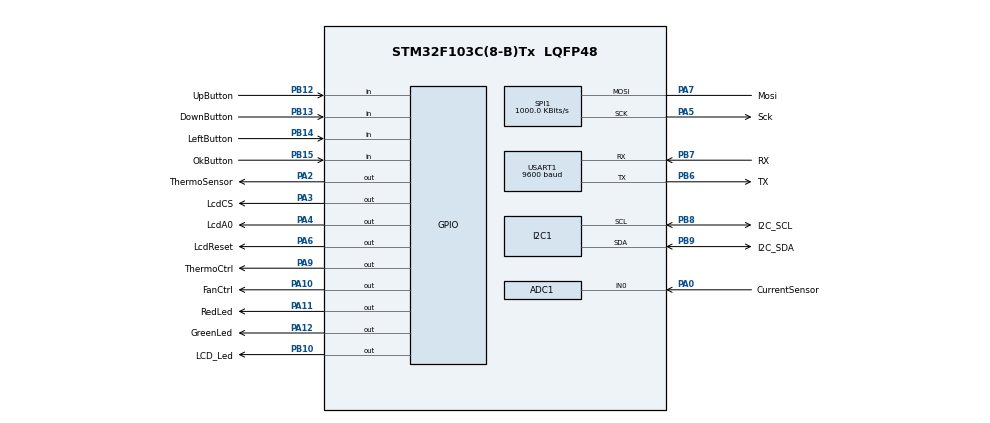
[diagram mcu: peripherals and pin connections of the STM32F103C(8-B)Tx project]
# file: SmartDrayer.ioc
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ADC1.Channel-0\#ChannelRegularConversion=ADC_CHANNEL_0
ADC1.NbrOfConversionFlag=1
ADC1.Rank-0\#ChannelRegularConversion=1
ADC1.SamplingTime-0\#ChannelRegularConversion=ADC_SAMPLETIME_1CYCLE_5
ADC1.master=1
Mcu.Family=STM32F1
Mcu.Name=STM32F103C(8-B)Tx
Mcu.Package=LQFP48
NVIC.PriorityGroup=NVIC_PRIORITYGROUP_4
NVIC.USART1_IRQn=true\:0\:0\:false\:false\:true\:true\:true
PA0-WKUP.GPIO_Label=CurrentSensor
PA0-WKUP.Signal=ADCx_IN0
PA10.GPIO_Label=FanCtrl
PA10.GPIO_Speed=GPIO_SPEED_FREQ_HIGH
PA10.Signal=GPIO_Output
PA11.GPIO_Label=RedLed
PA11.Signal=GPIO_Output
PA12.GPIO_Label=GreenLed
PA12.Signal=GPIO_Output
PA13.GPIO_Label=SWDIO
PA13.Mode=Serial_Wire
PA13.Signal=SYS_JTMS-SWDIO
PA14.GPIO_Label=SWCLK
PA14.Mode=Serial_Wire
PA14.Signal=SYS_JTCK-SWCLK
PA2.GPIO_Label=ThermoSensor
PA2.GPIO_Speed=GPIO_SPEED_FREQ_HIGH
PA2.PinState=GPIO_PIN_SET
PA2.Signal=GPIO_Output
PA3.GPIO_Label=LcdCS
PA3.GPIO_Speed=GPIO_SPEED_FREQ_HIGH
PA3.PinState=GPIO_PIN_SET
PA3.Signal=GPIO_Output
PA4.GPIO_Label=LcdA0
PA4.GPIO_Speed=GPIO_SPEED_FREQ_HIGH
PA4.Signal=GPIO_Output
PA5.GPIO_Label=Sck
PA5.Mode=Simplex_Bidirectional_Master
PA5.Signal=SPI1_SCK
PA6.GPIO_Label=LcdReset
PA6.GPIO_Speed=GPIO_SPEED_FREQ_HIGH
PA6.Signal=GPIO_Output
PA7.GPIO_Label=Mosi
PA7.Mode=Simplex_Bidirectional_Master
PA7.Signal=SPI1_MOSI
PA9.GPIO_Label=ThermoCtrl
PA9.Signal=GPIO_Output
PB10.GPIO_Label=LCD_Led
PB10.GPIO_Speed=GPIO_SPEED_FREQ_MEDIUM
PB10.Signal=GPIO_Output
PB12.GPIO_Label=UpButton
PB12.GPIO_PuPd=GPIO_PULLUP
PB12.Signal=GPIO_Input
PB13.GPIO_Label=DownButton
PB13.GPIO_PuPd=GPIO_PULLUP
PB13.Signal=GPIO_Input
PB14.GPIO_Label=LeftButton
PB14.GPIO_PuPd=GPIO_PULLUP
PB14.Signal=GPIO_Input
PB15.GPIO_Label=OkButton
PB15.GPIO_PuPd=GPIO_PULLUP
PB15.Signal=GPIO_Input
PB6.GPIO_Label=TX
PB6.Mode=Asynchronous
PB6.Signal=USART1_TX
PB7.GPIO_Label=RX
PB7.Mode=Asynchronous
PB7.Signal=USART1_RX
PB8.GPIO_Label=I2C_SCL
PB8.Mode=I2C
PB8.Signal=I2C1_SCL
PB9.GPIO_Label=I2C_SDA
PB9.Mode=I2C
PB9.Signal=I2C1_SDA
ProjectManager.HeapSize=0x200
ProjectManager.StackSize=0x400
ProjectManager.TargetToolchain=STM32CubeIDE
RCC.ADCPresc=RCC_ADCPCLK2_DIV6
RCC.AHBFreq_Value=64000000
RCC.APB1CLKDivider=RCC_HCLK_DIV2
RCC.APB1Freq_Value=32000000
RCC.APB1TimFreq_Value=64000000
RCC.APB2Freq_Value=64000000
RCC.APB2TimFreq_Value=64000000
RCC.HCLKFreq_Value=64000000
RCC.PLLMUL=RCC_PLL_MUL16
RCC.SYSCLKFreq_VALUE=64000000
RCC.SYSCLKSource=RCC_SYSCLKSOURCE_PLLCLK
RCC.USBFreq_Value=64000000
SH.ADCx_IN0.0=ADC1_IN0,IN0
SPI1.BaudRatePrescaler=SPI_BAUDRATEPRESCALER_64
SPI1.CalculateBaudRate=1000.0 KBits/s
SPI1.Direction=SPI_DIRECTION_1LINE
SPI1.Mode=SPI_MODE_MASTER
SPI1.VirtualType=VM_MASTER
TIM2.Period=65535 - 1
USART1.BaudRate=9600
USART1.VirtualMode=VM_ASYNC
VP_TIM2_VS_ClockSourceINT.Mode=Internal
board=custom

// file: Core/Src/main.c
/* USER CODE BEGIN Header */
/**
  ******************************************************************************
  * @file           : main.c
  * @brief          : Main program body
  ******************************************************************************
  * @attention
  *
  * <h2><center>&copy; Copyright (c) 2020 STMicroelectronics.
  * All rights reserved.</center></h2>
  *
  * This software component is licensed by ST under BSD 3-Clause license,
  * the "License"; You may not use this file except in compliance with the
  * License. You may obtain a copy of the License at:
  *                        opensource.org/licenses/BSD-3-Clause
  *
  ******************************************************************************
  */
/* USER CODE END Header */
#include "main.h"
#include "adc.h"
#include "i2c.h"
#include "spi.h"
#include "tim.h"
#include "usart.h"
#include "gpio.h"
//#include "Display.h"
//
//ST7920_LCD Display;

void SystemClock_Config(void);

int main(void)
{

  /* MCU Configuration--------------------------------------------------------*/

  /* Reset of all peripherals, Initializes the Flash interface and the Systick. */
  HAL_Init();

  /* Configure the system clock */
  SystemClock_Config();

  /* Initialize all configured peripherals */
  MX_GPIO_Init();
  MX_ADC1_Init();
  MX_I2C1_Init();
  MX_SPI1_Init();
  MX_TIM2_Init();
  MX_USART1_UART_Init();

  /* Infinite loop */
  while (1)
  {

  }
}

void SystemClock_Config(void)
{
  RCC_OscInitTypeDef RCC_OscInitStruct = {0};
  RCC_ClkInitTypeDef RCC_ClkInitStruct = {0};
  RCC_PeriphCLKInitTypeDef PeriphClkInit = {0};

  /** Initializes the RCC Oscillators according to the specified parameters
  * in the RCC_OscInitTypeDef structure.
  */
  RCC_OscInitStruct.OscillatorType = RCC_OSCILLATORTYPE_HSI;
  RCC_OscInitStruct.HSIState = RCC_HSI_ON;
  RCC_OscInitStruct.HSICalibrationValue = RCC_HSICALIBRATION_DEFAULT;
  RCC_OscInitStruct.PLL.PLLState = RCC_PLL_ON;
  RCC_OscInitStruct.PLL.PLLSource = RCC_PLLSOURCE_HSI_DIV2;
  RCC_OscInitStruct.PLL.PLLMUL = RCC_PLL_MUL6;
  if (HAL_RCC_OscConfig(&RCC_OscInitStruct) != HAL_OK)
  {
    Error_Handler();
  }
  /** Initializes the CPU, AHB and APB buses clocks
  */
  RCC_ClkInitStruct.ClockType = RCC_CLOCKTYPE_HCLK|RCC_CLOCKTYPE_SYSCLK
                              |RCC_CLOCKTYPE_PCLK1|RCC_CLOCKTYPE_PCLK2;
  RCC_ClkInitStruct.SYSCLKSource = RCC_SYSCLKSOURCE_PLLCLK;
  RCC_ClkInitStruct.AHBCLKDivider = RCC_SYSCLK_DIV1;
  RCC_ClkInitStruct.APB1CLKDivider = RCC_HCLK_DIV1;
  RCC_ClkInitStruct.APB2CLKDivider = RCC_HCLK_DIV1;

  if (HAL_RCC_ClockConfig(&RCC_ClkInitStruct, FLASH_LATENCY_0) != HAL_OK)
  {
    Error_Handler();
  }
  PeriphClkInit.PeriphClockSelection = RCC_PERIPHCLK_ADC;
  PeriphClkInit.AdcClockSelection = RCC_ADCPCLK2_DIV2;
  if (HAL_RCCEx_PeriphCLKConfig(&PeriphClkInit) != HAL_OK)
  {
    Error_Handler();
  }
}

void Error_Handler(void)
{
}

/************************ (C) COPYRIGHT STMicroelectronics *****END OF FILE****/
